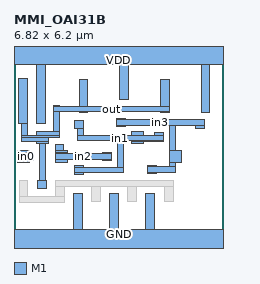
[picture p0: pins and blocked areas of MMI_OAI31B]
MACRO MMI_OAI31B
	CLASS CORE ;
	FOREIGN MMI_OAI31B 0 0 ;
	SIZE 6.82 BY 6.2 ;
	SYMMETRY X Y ;
	SITE CORE1 ;
	PIN out
		DIRECTION output ;
		USE SIGNAL ;
		PORT
			LAYER M1 ;
			RECT 0.16 3.865 0.44 5.335 ;
			LAYER M1 ;
			RECT 0.25 3.465 0.44 3.865 ;
			LAYER M1 ;
			RECT 1.29 4.435 1.485 4.445 ;
			LAYER M1 ;
			RECT 2.125 4.435 2.405 5.315 ;
			LAYER M1 ;
			RECT 4.785 4.435 5.065 5.315 ;
			LAYER M1 ;
			RECT 1.29 4.245 5.065 4.435 ;
			LAYER M1 ;
			RECT 1.29 3.6 1.485 4.245 ;
			LAYER M1 ;
			RECT 2.125 4.23 2.405 4.245 ;
			LAYER M1 ;
			RECT 4.785 4.23 5.065 4.245 ;
			LAYER M1 ;
			RECT 0.74 3.465 1.485 3.6 ;
			LAYER M1 ;
			RECT 0.25 3.405 1.485 3.465 ;
			LAYER M1 ;
			RECT 0.25 3.27 1.12 3.405 ;
			LAYER M1 ;
			RECT 0.74 3.22 1.12 3.27 ;
			LAYER M1 ;
			RECT 0.845 2.01 1.04 3.22 ;
			LAYER M1 ;
			RECT 0.765 1.73 1.045 2.01 ;
		END
		AntennaDiffArea 1.9635 ;
	END out
	PIN in1
		DIRECTION input ;
		USE SIGNAL ;
		PORT
			LAYER M1 ;
			RECT 1.99 3.7 2.27 3.98 ;
			LAYER M1 ;
			RECT 2.08 3.49 2.27 3.7 ;
			LAYER M1 ;
			RECT 3.84 3.49 4.22 3.6 ;
			LAYER M1 ;
			RECT 2.08 3.465 4.22 3.49 ;
			LAYER M1 ;
			RECT 4.59 3.465 4.87 3.57 ;
			LAYER M1 ;
			RECT 2.08 3.3 4.87 3.465 ;
			LAYER M1 ;
			RECT 1.99 2.445 2.27 2.49 ;
			LAYER M1 ;
			RECT 3.37 2.445 3.565 3.3 ;
			LAYER M1 ;
			RECT 3.84 3.29 4.87 3.3 ;
			LAYER M1 ;
			RECT 3.84 3.27 4.8 3.29 ;
			LAYER M1 ;
			RECT 3.84 3.22 4.22 3.27 ;
			LAYER M1 ;
			RECT 1.99 2.255 3.565 2.445 ;
			LAYER M1 ;
			RECT 1.99 2.21 2.27 2.255 ;
		END
		AntennaGateArea 0.924 ;
	END in1
	PIN GND
		DIRECTION inout ;
		USE GROUND ;
		PORT
			LAYER M1 ;
			RECT 1.945 0.42 2.225 1.59 ;
			LAYER M1 ;
			RECT 3.125 0.42 3.405 1.59 ;
			LAYER M1 ;
			RECT 4.305 0.42 4.585 1.59 ;
			LAYER M1 ;
			RECT 0 -0.42 6.82 0.42 ;
		END
	END GND
	PIN in2
		DIRECTION input ;
		USE SIGNAL ;
		PORT
			LAYER M1 ;
			RECT 1.35 2.98 1.63 3.19 ;
			LAYER M1 ;
			RECT 1.35 2.91 1.74 2.98 ;
			LAYER M1 ;
			RECT 1.36 2.885 1.74 2.91 ;
			LAYER M1 ;
			RECT 2.89 2.885 3.17 2.93 ;
			LAYER M1 ;
			RECT 1.36 2.695 3.17 2.885 ;
			LAYER M1 ;
			RECT 1.36 2.6 1.74 2.695 ;
			LAYER M1 ;
			RECT 2.89 2.65 3.17 2.695 ;
		END
		AntennaGateArea 0.924 ;
	END in2
	PIN VDD
		DIRECTION inout ;
		USE POWER ;
		PORT
			LAYER M1 ;
			RECT 0 5.78 6.82 6.62 ;
			LAYER M1 ;
			RECT 0.75 3.865 1.03 5.78 ;
			LAYER M1 ;
			RECT 3.455 4.64 3.735 5.78 ;
			LAYER M1 ;
			RECT 6.115 4.23 6.395 5.78 ;
		END
	END VDD
	PIN in3
		DIRECTION input ;
		USE SIGNAL ;
		PORT
			LAYER M1 ;
			RECT 3.355 3.995 3.635 4.045 ;
			LAYER M1 ;
			RECT 3.355 3.805 6.2 3.995 ;
			LAYER M1 ;
			RECT 3.355 3.765 3.635 3.805 ;
			LAYER M1 ;
			RECT 5.08 2.98 5.275 3.805 ;
			LAYER M1 ;
			RECT 5.92 3.715 6.2 3.805 ;
			LAYER M1 ;
			RECT 5.08 2.6 5.46 2.98 ;
			LAYER M1 ;
			RECT 4.355 2.465 4.635 2.51 ;
			LAYER M1 ;
			RECT 5.08 2.465 5.275 2.6 ;
			LAYER M1 ;
			RECT 4.355 2.275 5.275 2.465 ;
			LAYER M1 ;
			RECT 4.355 2.23 4.635 2.275 ;
		END
		AntennaGateArea 0.924 ;
	END in3
	PIN in0
		DIRECTION input ;
		USE SIGNAL ;
		PORT
			LAYER M1 ;
			RECT 0.12 2.93 0.5 2.98 ;
			LAYER M1 ;
			RECT 0.12 2.65 0.635 2.93 ;
			LAYER M1 ;
			RECT 0.12 2.6 0.5 2.65 ;
		END
		AntennaGateArea 0.462 ;
	END in0
	OBS
		LAYER M1 ;
		RECT 0.175 1.5 0.455 2.01 ;
		LAYER M1 ;
		RECT 1.355 1.82 5.19 2.01 ;
		LAYER M1 ;
		RECT 1.355 1.5 1.635 1.82 ;
		LAYER M1 ;
		RECT 0.17 1.305 1.64 1.5 ;
		LAYER M1 ;
		RECT 2.535 1.31 2.815 1.82 ;
		LAYER M1 ;
		RECT 3.715 1.31 3.995 1.82 ;
		LAYER M1 ;
		RECT 4.91 1.31 5.19 1.82 ;
	END
END MMI_OAI31B
